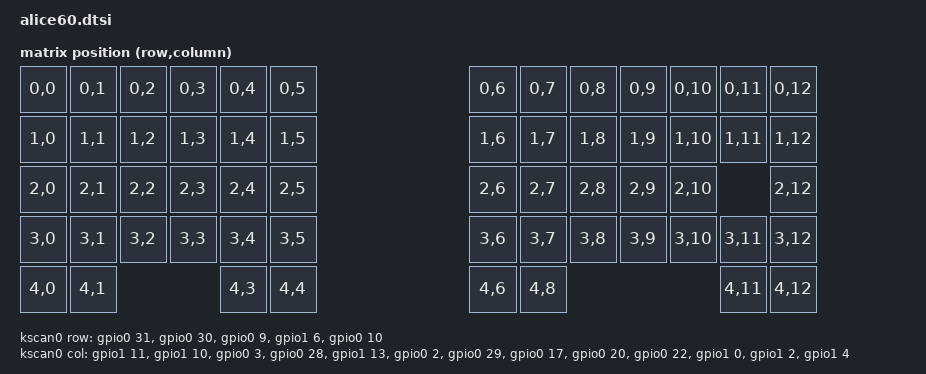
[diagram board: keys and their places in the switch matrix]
/*
 * Copyright (c) 2020 The ZMK Contributors
 *
 * SPDX-License-Identifier: MIT
 */

#include <dt-bindings/zmk/matrix_transform.h>
#include <physical_layouts.dtsi>
#include <dt-bindings/led/led.h>

/ {
	chosen {
		zmk,kscan = &kscan0;
                                zmk,physical-layout - &openwork36;
		zmk,matrix_transform = &default_transform;
		zmk,underglow = &led_strip;
	};

	kscan0: kscan {
		compatible = "zmk,kscan-gpio-matrix";
		label = "KSCAN";

		diode-direction = "col2row";
		col-gpios
			= <&gpio1 11 GPIO_ACTIVE_HIGH>
			, <&gpio1 10 GPIO_ACTIVE_HIGH>
			, <&gpio0 3 GPIO_ACTIVE_HIGH>
			, <&gpio0 28 GPIO_ACTIVE_HIGH>
			, <&gpio1 13 GPIO_ACTIVE_HIGH>
			, <&gpio0 2 GPIO_ACTIVE_HIGH>
			, <&gpio0 29 GPIO_ACTIVE_HIGH>
			, <&gpio0 17 GPIO_ACTIVE_HIGH>
			, <&gpio0 20 GPIO_ACTIVE_HIGH>
			, <&gpio0 22 GPIO_ACTIVE_HIGH>
			, <&gpio1 0 GPIO_ACTIVE_HIGH>
			, <&gpio1 2 GPIO_ACTIVE_HIGH>
			, <&gpio1 4 GPIO_ACTIVE_HIGH>
			;
		row-gpios
			= <&gpio0 31 (GPIO_ACTIVE_HIGH | GPIO_PULL_DOWN)>
			, <&gpio0 30 (GPIO_ACTIVE_HIGH | GPIO_PULL_DOWN)>
			, <&gpio0 9 (GPIO_ACTIVE_HIGH | GPIO_PULL_DOWN)>
			, <&gpio1 6 (GPIO_ACTIVE_HIGH | GPIO_PULL_DOWN)>
			, <&gpio0 10 (GPIO_ACTIVE_HIGH | GPIO_PULL_DOWN)>
			;
	};

	default_transform: keymap_transform_0 {
		compatible = "zmk,matrix-transform";
		columns = <13>;
		rows = <5>;
        map = <
        RC(0,0) RC(0,1) RC(0,2) RC(0,3) RC(0,4) RC(0,5) RC(0,6) RC(0,7) RC(0,8) RC(0,9) RC(0,10) RC(0,11) RC(0,12) 
        RC(1,0) RC(1,1) RC(1,2) RC(1,3) RC(1,4) RC(1,5) RC(1,6) RC(1,7) RC(1,8) RC(1,9) RC(1,10) RC(1,11) RC(1,12) 
        RC(2,0) RC(2,1) RC(2,2) RC(2,3) RC(2,4) RC(2,5) RC(2,6) RC(2,7) RC(2,8) RC(2,9) RC(2,10)          RC(2,12) 
        RC(3,0) RC(3,1) RC(3,2) RC(3,3) RC(3,4) RC(3,5) RC(3,6) RC(3,7) RC(3,8) RC(3,9) RC(3,10) RC(3,11) RC(3,12)
        RC(4,0) RC(4,1)         RC(4,3) RC(4,4)         RC(4,6)         RC(4,8)                  RC(4,11) RC(4,12)
		>;
	};
};
&pinctrl {
    spi3_default: spi3_default {
        group1 {
            psels = <NRF_PSEL(SPIM_MOSI, 0, 6)>;
        };
    };

    spi3_sleep: spi3_sleep {
        group1 {
            psels = <NRF_PSEL(SPIM_MOSI, 0, 6)>;
            low-power-enable;
        };
    };
};

&spi3 {
  compatible = "nordic,nrf-spim";
  status = "okay";

  pinctrl-0 = <&spi3_default>;
  pinctrl-1 = <&spi3_sleep>;
  pinctrl-names = "default", "sleep";

  led_strip: ws2812@0 {
    compatible = "worldsemi,ws2812-spi";
    label = "WS2812";

    /* SPI */
    reg = <0>; /* ignored, but necessary for SPI bindings */
    spi-max-frequency = <4000000>;

    /* WS2812 */
    chain-length = <5>; /* number of LEDs */
    spi-one-frame = <0x70>;
    spi-zero-frame = <0x40>;
    color-mapping = <LED_COLOR_ID_GREEN
                          LED_COLOR_ID_RED
                          LED_COLOR_ID_BLUE>;

/ {
    physical_layout0: physical_layout_0 {
        compatible = "zmk,physical-layout";
        display-name = "LAYOUT";

        kscan = <&kscan0>;
        transform = <&matrix_transform0>;

        keys  //                     w   h    x    y     rot    rx    ry
            = <&key_physical_attrs 100 100    0    0       0     0     0>
            , <&key_physical_attrs 100 100  100    0       0     0     0>
            , <&key_physical_attrs 100 100  200    0       0     0     0>
            , <&key_physical_attrs 100 100  300    0       0     0     0>
            , <&key_physical_attrs 100 100  400    0       0     0     0>
            , <&key_physical_attrs 100 100  500    0       0     0     0>
            , <&key_physical_attrs 100 100  900    0       0     0     0>
            , <&key_physical_attrs 100 100 1000    0       0     0     0>
            , <&key_physical_attrs 100 100 1100    0       0     0     0>
            , <&key_physical_attrs 100 100 1200    0       0     0     0>
            , <&key_physical_attrs 100 100 1300    0       0     0     0>
            , <&key_physical_attrs 100 100 1400    0       0     0     0>
            , <&key_physical_attrs 100 100 1500    0       0     0     0>
            , <&key_physical_attrs 100 100    0  100       0     0     0>
            , <&key_physical_attrs 100 100  100  100       0     0     0>
            , <&key_physical_attrs 100 100  200  100       0     0     0>
            , <&key_physical_attrs 100 100  300  100       0     0     0>
            , <&key_physical_attrs 100 100  400  100       0     0     0>
            , <&key_physical_attrs 100 100  500  100       0     0     0>
            , <&key_physical_attrs 100 100  900  100       0     0     0>
            , <&key_physical_attrs 100 100 1000  100       0     0     0>
            , <&key_physical_attrs 100 100 1100  100       0     0     0>
            , <&key_physical_attrs 100 100 1200  100       0     0     0>
            , <&key_physical_attrs 100 100 1300  100       0     0     0>
            , <&key_physical_attrs 100 100 1400  100       0     0     0>
            , <&key_physical_attrs 100 100 1500  100       0     0     0>
            , <&key_physical_attrs 100 100    0  200       0     0     0>
            , <&key_physical_attrs 100 100  100  200       0     0     0>
            , <&key_physical_attrs 100 100  200  200       0     0     0>
            , <&key_physical_attrs 100 100  300  200       0     0     0>
            , <&key_physical_attrs 100 100  400  200       0     0     0>
            , <&key_physical_attrs 100 100  500  200       0     0     0>
            , <&key_physical_attrs 100 100  900  200       0     0     0>
            , <&key_physical_attrs 100 100 1000  200       0     0     0>
            , <&key_physical_attrs 100 100 1100  200       0     0     0>
            , <&key_physical_attrs 100 100 1200  200       0     0     0>
            , <&key_physical_attrs 100 100 1300  200       0     0     0>
            , <&key_physical_attrs 100 100 1500  200       0     0     0>
            , <&key_physical_attrs 100 100    0  300       0     0     0>
            , <&key_physical_attrs 100 100  100  300       0     0     0>
            , <&key_physical_attrs 100 100  200  300       0     0     0>
            , <&key_physical_attrs 100 100  300  300       0     0     0>
            , <&key_physical_attrs 100 100  400  300       0     0     0>
            , <&key_physical_attrs 100 100  500  300       0     0     0>
            , <&key_physical_attrs 100 100  900  300       0     0     0>
            , <&key_physical_attrs 100 100 1000  300       0     0     0>
            , <&key_physical_attrs 100 100 1100  300       0     0     0>
            , <&key_physical_attrs 100 100 1200  300       0     0     0>
            , <&key_physical_attrs 100 100 1300  300       0     0     0>
            , <&key_physical_attrs 100 100 1400  300       0     0     0>
            , <&key_physical_attrs 100 100 1500  300       0     0     0>
            , <&key_physical_attrs 100 100    0  400       0     0     0>
            , <&key_physical_attrs 100 100  100  400       0     0     0>
            , <&key_physical_attrs 100 100  400  400       0     0     0>
            , <&key_physical_attrs 100 100  500  400       0     0     0>
            , <&key_physical_attrs 100 100  900  400       0     0     0>
            , <&key_physical_attrs 100 100 1000  400       0     0     0>
            , <&key_physical_attrs 100 100 1400  400       0     0     0>
            , <&key_physical_attrs 100 100 1500  400       0     0     0>
            ;
    
  };
};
